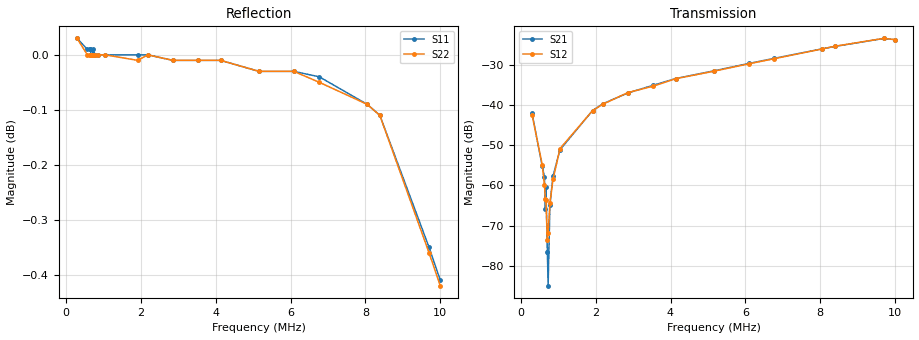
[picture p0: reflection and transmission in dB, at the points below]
!s-Parameter Generated by FASTRON Sdn. Bhd.
!FASTRON P/N : 1812AFTC-602X
!Keysight Technologies: E5071C_MY46733604_B.14.02
!Date: Wed Mar 18 14:03:45 2026
!Version  :Rev00  Wed Mar 18 14:03:45 2026
!Data & Calibration Information:
!Freq  S11:SOLT2(ON)  S21:SOLT2(ON)  S12:SOLT2(ON)  S22:SOLT2(ON)
!PortZ  Port1:50+j0  Port2:50+j0
!When reading reference impedance value at option line is always used.
! Remarks : This data is being provided solely for informational purposes.
# Hz S dB R 50
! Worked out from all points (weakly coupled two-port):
!   1601 points, 300 kHz to 10 MHz, reference 50 ohm
!   highest |S21| = -23.47 dB at 9.7 MHz (marker M1); lowest = -84.9 dB at 730.2 kHz (marker M2)
!   lowest |S11| = -0.4 dB at 10 MHz (marker M3), VSWR 42.23, Z = 21.3 - j205 ohm
!   |S11| at or under -10 dB: nowhere
!   |S22| runs from -0.4 to 0.0 dB; largest |S21 - S12| = 0.00074
!   S11 on the Smith chart (normalised r, x): 300 kHz: -0, +11; 2.19 MHz: 0.00, +1.35; 4.134 MHz: 0.00, +0.39; 6.088 MHz: 0.00, -0.20; 8.047 MHz: 0.01, -0.95; 10 MHz: 0.43, -4.11
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300000  0.03 10.2  -42.06 -87.0  -42.41 -86.6  0.03 -10.9
573527  0.01 19.2  -55.23 -85.2  -54.86 -81.6  0.00 -21.2
632106  0.01 21.1  -57.83 -81.5  -59.97 -82.8  0.00 -23.3
657003  0.01 21.9  -65.76 -49.9  -63.34 -70.4  0.00 -24.3
671648  0.00 22.4  -60.39 -74.2  -63.66 -71.7  0.00 -24.8
709724  0.00 23.7  -76.41 -123.1  -73.45 -44.2  0.00 -26.2
730227  0.01 24.3  -84.89 40.8  -71.79 3.6  0.00 -26.9
778555  0.00 25.9  -64.79 53.9  -64.39 64.6  0.00 -28.7
860293  0.00 28.7  -57.67 74.9  -58.51 78.1  -0.00 -31.8
1047634  0.00 34.9  -51.13 85.5  -50.84 84.2  0.00 -38.7
1917564  -0.00 63.8  -41.38 83.7  -41.40 83.8  -0.01 -70.9
2189863  -0.00 72.9  -39.72 83.7  -39.83 83.0  -0.00 -80.9
2856713  -0.01 95.0  -37.03 82.0  -36.95 81.9  -0.01 -105.6
3534704  -0.01 117.6  -35.12 78.9  -35.33 79.3  -0.01 -130.7
4133799  -0.01 137.5  -33.45 78.0  -33.49 78.8  -0.01 -152.8
5155786  -0.03 171.5  -31.53 74.2  -31.62 74.4  -0.03 169.4
6087954  -0.03 -157.6  -29.70 73.3  -29.79 73.4  -0.03 134.9
6770355  -0.04 -135.0  -28.42 71.3  -28.51 71.5  -0.05 109.6
8047393  -0.09 -92.8  -26.07 64.4  -26.09 64.5  -0.09 62.1
8385344  -0.11 -81.6  -25.47 61.3  -25.43 61.4  -0.11 49.5
9699599  -0.35 -37.7  -23.47 36.7  -23.46 36.7  -0.36 1.1
1e7  -0.41 -27.1  -23.79 27.1  -23.78 27.1  -0.42 -9.4
